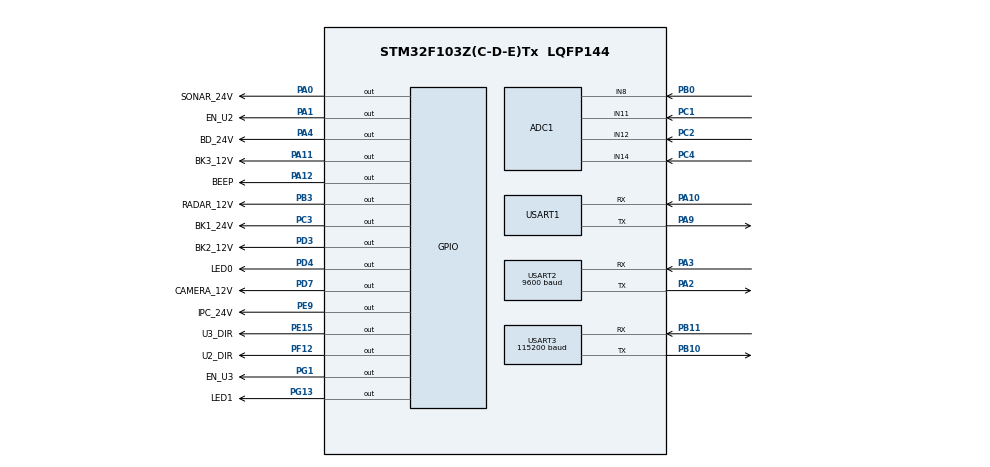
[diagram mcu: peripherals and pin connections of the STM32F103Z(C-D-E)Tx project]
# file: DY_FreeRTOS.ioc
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ADC1.ContinuousConvMode=DISABLE
ADC1.EnableRegularConversion=DISABLE
ADC1.master=1
FREERTOS.Tasks01=defaultTask,24,128,StartDefaultTask,Default,NULL,Dynamic,NULL,NULL
FREERTOS.configTOTAL_HEAP_SIZE=15360
IWDG.Prescaler=IWDG_PRESCALER_64
IWDG.Reload=2500
Mcu.Family=STM32F1
Mcu.Name=STM32F103Z(C-D-E)Tx
Mcu.Package=LQFP144
NVIC.PriorityGroup=NVIC_PRIORITYGROUP_4
NVIC.TIM4_IRQn=true\:15\:0\:false\:false\:true\:false\:false\:true\:true
NVIC.TimeBase=TIM4_IRQn
NVIC.TimeBaseIP=TIM4
NVIC.USART2_IRQn=true\:5\:0\:false\:false\:true\:true\:true\:true\:true
OSC_IN.Mode=HSE-External-Oscillator
OSC_IN.Signal=RCC_OSC_IN
OSC_OUT.Mode=HSE-External-Oscillator
OSC_OUT.Signal=RCC_OSC_OUT
PA0-WKUP.GPIO_Label=SONAR_24V
PA0-WKUP.Signal=GPIO_Output
PA1.GPIO_Label=EN_U2
PA1.Signal=GPIO_Output
PA10.Mode=Asynchronous
PA10.Signal=USART1_RX
PA11.GPIO_Label=BK3_12V
PA11.Signal=GPIO_Output
PA12.GPIO_Label=BEEP
PA12.PinState=GPIO_PIN_SET
PA12.Signal=GPIO_Output
PA13.Mode=Serial_Wire
PA13.Signal=SYS_JTMS-SWDIO
PA14.Mode=Serial_Wire
PA14.Signal=SYS_JTCK-SWCLK
PA2.Mode=Asynchronous
PA2.Signal=USART2_TX
PA3.Mode=Asynchronous
PA3.Signal=USART2_RX
PA4.GPIO_Label=BD_24V
PA4.Signal=GPIO_Output
PA9.Mode=Asynchronous
PA9.Signal=USART1_TX
PB0.Signal=ADCx_IN8
PB10.Mode=Asynchronous
PB10.Signal=USART3_TX
PB11.Mode=Asynchronous
PB11.Signal=USART3_RX
PB3.GPIO_Label=RADAR_12V
PB3.Signal=GPIO_Output
PC1.Signal=ADCx_IN11
PC14-OSC32_IN.Mode=LSE-External-Oscillator
PC14-OSC32_IN.Signal=RCC_OSC32_IN
PC15-OSC32_OUT.Mode=LSE-External-Oscillator
PC15-OSC32_OUT.Signal=RCC_OSC32_OUT
PC2.Signal=ADCx_IN12
PC3.GPIO_Label=BK1_24V
PC3.Signal=GPIO_Output
PC4.Signal=ADCx_IN14
PD3.GPIO_Label=BK2_12V
PD3.Signal=GPIO_Output
PD4.GPIO_Label=LED0
PD4.GPIO_ModeDefaultOutputPP=GPIO_MODE_OUTPUT_PP
PD4.Signal=GPIO_Output
PD7.GPIO_Label=CAMERA_12V
PD7.Signal=GPIO_Output
PE15.GPIO_Label=U3_DIR
PE15.Signal=GPIO_Output
PE9.GPIO_Label=IPC_24V
PE9.Signal=GPIO_Output
PF12.GPIO_Label=U2_DIR
PF12.Signal=GPIO_Output
PG1.GPIO_Label=EN_U3
PG1.Signal=GPIO_Output
PG13.GPIO_Label=LED1
PG13.GPIO_ModeDefaultOutputPP=GPIO_MODE_OUTPUT_PP
PG13.Signal=GPIO_Output
ProjectManager.HeapSize=0x200
ProjectManager.StackSize=0x400
ProjectManager.TargetToolchain=MDK-ARM V5.32
RCC.ADCPresc=RCC_ADCPCLK2_DIV6
RCC.AHBFreq_Value=72000000
RCC.APB1CLKDivider=RCC_HCLK_DIV2
RCC.APB1Freq_Value=36000000
RCC.APB1TimFreq_Value=72000000
RCC.APB2Freq_Value=72000000
RCC.APB2TimFreq_Value=72000000
RCC.HCLKFreq_Value=72000000
RCC.PLLMUL=RCC_PLL_MUL9
RCC.PLLSourceVirtual=RCC_PLLSOURCE_HSE
RCC.RTCClockSelection=RCC_RTCCLKSOURCE_LSE
RCC.SYSCLKFreq_VALUE=72000000
RCC.SYSCLKSource=RCC_SYSCLKSOURCE_PLLCLK
RCC.USBFreq_Value=72000000
SH.ADCx_IN11.0=ADC1_IN11,IN11
SH.ADCx_IN12.0=ADC1_IN12,IN12
SH.ADCx_IN14.0=ADC1_IN14,IN14
SH.ADCx_IN8.0=ADC1_IN8,IN8
USART1.VirtualMode=VM_ASYNC
USART2.BaudRate=9600
USART2.VirtualMode=VM_ASYNC
USART3.BaudRate=115200
USART3.VirtualMode=VM_ASYNC
VP_FREERTOS_VS_CMSIS_V2.Mode=CMSIS_V2
VP_IWDG_VS_IWDG.Mode=IWDG_Activate
VP_RTC_VS_RTC_Activate.Mode=RTC_Enabled
VP_RTC_VS_RTC_Calendar.Mode=RTC_Calendar
VP_SYS_VS_tim4.Mode=TIM4
board=custom

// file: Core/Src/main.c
/* USER CODE BEGIN Header */
/**
  ******************************************************************************
  * @file           : main.c
  * @brief          : Main program body
  ******************************************************************************
  * @attention
  *
  * Copyright (c) 2026 STMicroelectronics.
  * All rights reserved.
  *
  * This software is licensed under terms that can be found in the LICENSE file
  * in the root directory of this software component.
  * If no LICENSE file comes with this software, it is provided AS-IS.
  *
  ******************************************************************************
  */
/* USER CODE END Header */
#include "main.h"
#include "cmsis_os.h"
#include "adc.h"
#include "iwdg.h"
#include "rtc.h"
#include "usart.h"
#include "gpio.h"

/* USER CODE BEGIN Includes */
#include "board.h"
#include "log.h"
#include "monitor_service.h"
#include "time_service.h"
#include "delay_us.h"
#include "rule_store.h"
#include "power.h"
#include "power_apply.h"
#include "uart485.h"
#include "lora_softuart.h"
#include "protocol.h"
#include "wdg_service.h"
/* USER CODE END Includes */

void SystemClock_Config(void);
void MX_FREERTOS_Init(void);

int main(void)
{

  /* MCU Configuration--------------------------------------------------------*/

  /* Reset of all peripherals, Initializes the Flash interface and the Systick. */
  HAL_Init();

  /* Configure the system clock */
  SystemClock_Config();

  /* Initialize all configured peripherals */
  MX_GPIO_Init();
  MX_USART1_UART_Init();
  MX_USART2_UART_Init();
  MX_USART3_UART_Init();
  MX_ADC1_Init();
  MX_RTC_Init();
  MX_IWDG_Init();
  /* USER CODE BEGIN 2 */
  /*==============================
   *  #1. 板级与各服务初始化（必须早于启动调度器）
   *==============================*/
  board_init();                                         // 8 台设备断电，12V 总控保持接通
  log_init();                                           // 日志队列与串口互斥量
  delay_us_init();                                      // 微秒延时（软件 I2C 依赖）
  rule_store_init();                                    // EEPROM 与规则存储
  time_service_init();                                  // 时间服务（基于 RTC，须早于使用时间的功能）
  power_init();                                         // 供电决策层（载入规则表）
  uart485_init();                                       // 485 方向控制与发送互斥量
  uart485_start_rx();                                   // 启动 USART2 接收中断
    lora_init();                                          // LoRa 软串口（现场调试通道）
  power_apply_init();                                   // 供电执行层（输出状态清零）
  protocol_init();                                      // 协议层状态复位
  wdg_service_init();                                   // 看门狗心跳事件组

  if (monitor_service_init() == false)
  {
      Error_Handler();                                  // 监控服务初始化失败
  }

  /* USER CODE END 2 */

  /* Init scheduler */
  osKernelInitialize();  /* Call init function for freertos objects (in cmsis_os2.c) */
  MX_FREERTOS_Init();

  /* Start scheduler */
  osKernelStart();

  /* We should never get here as control is now taken by the scheduler */

  /* Infinite loop */
  while (1)
  {

  }
}

void SystemClock_Config(void)
{
  RCC_OscInitTypeDef RCC_OscInitStruct = {0};
  RCC_ClkInitTypeDef RCC_ClkInitStruct = {0};
  RCC_PeriphCLKInitTypeDef PeriphClkInit = {0};

  /** Initializes the RCC Oscillators according to the specified parameters
  * in the RCC_OscInitTypeDef structure.
  */
  RCC_OscInitStruct.OscillatorType = RCC_OSCILLATORTYPE_LSI|RCC_OSCILLATORTYPE_HSE
                              |RCC_OSCILLATORTYPE_LSE;
  RCC_OscInitStruct.HSEState = RCC_HSE_ON;
  RCC_OscInitStruct.HSEPredivValue = RCC_HSE_PREDIV_DIV1;
  RCC_OscInitStruct.LSEState = RCC_LSE_ON;
  RCC_OscInitStruct.HSIState = RCC_HSI_ON;
  RCC_OscInitStruct.LSIState = RCC_LSI_ON;
  RCC_OscInitStruct.PLL.PLLState = RCC_PLL_ON;
  RCC_OscInitStruct.PLL.PLLSource = RCC_PLLSOURCE_HSE;
  /* ⚠ 低功耗改动：PLL 倍频由 x9 改为 x4，主频 72MHz -> 32MHz（HSE 8MHz × 4）
       目的：运行电流约降一半（约 36mA -> 18mA），配合 tickless idle 进一步降功耗。
       说明：本芯片（STM32F103）的 PLLMUL 只有整数倍频（x2~x16），不支持 x4.5，
             故无法精确得到 36MHz，取最接近的 32MHz（比 36MHz 更省电）。
       LoRa 软串口的微秒延时基于 DWT + SystemCoreClock 换算，降频后自动适配，
       时序不受影响（详见 docs/低功耗实现说明.md）。
       ⚠ CubeMX 重新生成代码会覆盖此处，需重新改回 RCC_PLL_MUL4。 */
  RCC_OscInitStruct.PLL.PLLMUL = RCC_PLL_MUL4;
  if (HAL_RCC_OscConfig(&RCC_OscInitStruct) != HAL_OK)
  {
    Error_Handler();
  }

  /** Initializes the CPU, AHB and APB buses clocks
  */
  RCC_ClkInitStruct.ClockType = RCC_CLOCKTYPE_HCLK|RCC_CLOCKTYPE_SYSCLK
                              |RCC_CLOCKTYPE_PCLK1|RCC_CLOCKTYPE_PCLK2;
  RCC_ClkInitStruct.SYSCLKSource = RCC_SYSCLKSOURCE_PLLCLK;
  RCC_ClkInitStruct.AHBCLKDivider = RCC_SYSCLK_DIV1;
  RCC_ClkInitStruct.APB1CLKDivider = RCC_HCLK_DIV2;
  RCC_ClkInitStruct.APB2CLKDivider = RCC_HCLK_DIV1;

  /* ⚠ 低功耗改动：主频降到 36MHz 后只需 1 个 Flash 等待周期（0-24MHz 用 0WS，24-48MHz 用 1WS，48-72MHz 用 2WS） */
  if (HAL_RCC_ClockConfig(&RCC_ClkInitStruct, FLASH_LATENCY_1) != HAL_OK)
  {
    Error_Handler();
  }
  PeriphClkInit.PeriphClockSelection = RCC_PERIPHCLK_RTC|RCC_PERIPHCLK_ADC;
  PeriphClkInit.RTCClockSelection = RCC_RTCCLKSOURCE_LSE;
  PeriphClkInit.AdcClockSelection = RCC_ADCPCLK2_DIV6;
  if (HAL_RCCEx_PeriphCLKConfig(&PeriphClkInit) != HAL_OK)
  {
    Error_Handler();
  }
}

void HAL_TIM_PeriodElapsedCallback(TIM_HandleTypeDef *htim)
{
  if (htim->Instance == TIM4)
  {
    HAL_IncTick();
  }
}

void Error_Handler(void)
{
  __disable_irq();
  while (1)
  {
  }
}

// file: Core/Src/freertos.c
/* USER CODE BEGIN Header */
/**
  ******************************************************************************
  * File Name          : freertos.c
  * Description        : Code for freertos applications
  ******************************************************************************
  * @attention
  *
  * Copyright (c) 2026 STMicroelectronics.
  * All rights reserved.
  *
  * This software is licensed under terms that can be found in the LICENSE file
  * in the root directory of this software component.
  * If no LICENSE file comes with this software, it is provided AS-IS.
  *
  ******************************************************************************
  */
/* USER CODE END Header */

#include "FreeRTOS.h"
#include "task.h"
#include "main.h"
#include "cmsis_os.h"

/* USER CODE BEGIN Includes */
#include <stdio.h>
#include "usart.h"
#include "tasks.h"
#include "board.h"
#include "sense.h"
#include "log.h"
/* USER CODE BEGIN Includes */
                     // 日志服务
/* USER CODE END Includes */

/* Definitions for defaultTask */
osThreadId_t defaultTaskHandle;
const osThreadAttr_t defaultTask_attributes = {
  .name = "defaultTask",
  .stack_size = 128 * 4,
  .priority = (osPriority_t) osPriorityNormal,
};

/* USER CODE BEGIN FunctionPrototypes */
/* 带失败检查的任务创建接口（创建失败会打印原因） */
void app_task_create(TaskFunction_t fn, const char *name, uint16_t stack, UBaseType_t prio);

/* USER CODE END FunctionPrototypes */

void StartDefaultTask(void *argument);

void MX_FREERTOS_Init(void); /* (MISRA C 2004 rule 8.1) */

void MX_FREERTOS_Init(void) {
  /* USER CODE BEGIN Init */
  /* 用带检查的接口创建任务：任一失败都会打印原因（通常是堆内存不足） */
  app_task_create(TaskHeartbeat, TASK_HEARTBEAT_NAME, TASK_HEARTBEAT_STACK, TASK_HEARTBEAT_PRIO);
  app_task_create(TaskMonitor,   TASK_MONITOR_NAME,   TASK_MONITOR_STACK,   TASK_MONITOR_PRIO);
  app_task_create(TaskLog,       TASK_LOG_NAME,       TASK_LOG_STACK,       TASK_LOG_PRIO);
  app_task_create(TaskSelfTest,  TASK_SELFTEST_NAME,  TASK_SELFTEST_STACK,  TASK_SELFTEST_PRIO);
  app_task_create(TaskPower,     TASK_POWER_NAME,     TASK_POWER_STACK,     TASK_POWER_PRIO);
  app_task_create(TaskComm,      TASK_COMM_NAME,      TASK_COMM_STACK,      TASK_COMM_PRIO);
  app_task_create(TaskWdg,       TASK_WDG_NAME,       TASK_WDG_STACK,       TASK_WDG_PRIO);
  /* USER CODE END Init */

  /* Create the thread(s) */
  /* creation of defaultTask */
  defaultTaskHandle = osThreadNew(StartDefaultTask, NULL, &defaultTask_attributes);

}

void StartDefaultTask(void *argument)
{
  /* USER CODE BEGIN StartDefaultTask */
  vTaskSuspend(NULL);
  /* Infinite loop */
  for(;;)
  {
    osDelay(1);
  }

  /* USER CODE END StartDefaultTask */
}

/* USER CODE BEGIN Application */
/*******************************************************************************
 * 函数名：app_task_create
 * 功  能：创建任务并检查结果
 * 参  数：fn —— 任务函数；name —— 任务名；stack —— 栈（字）；prio —— 优先级
 * 返回值：无
 * 说  明：创建失败通常意味着 FreeRTOS 堆内存不足，必须打印出来；
 *         否则任务会“静默缺失”，现象是功能完全没反应却查不出原因
 ******************************************************************************/
void app_task_create(TaskFunction_t fn, const char *name, uint16_t stack, UBaseType_t prio)
{
  /*==============================
   *  #1. 创建任务并检查返回值
   *==============================*/
  if (xTaskCreate(fn, name, stack, NULL, prio, NULL) != pdPASS)
  {
    printf("[ERROR] 创建任务 %s 失败：FreeRTOS 堆内存不足\r\n", name);
  }
}

/* USER CODE END Application */
